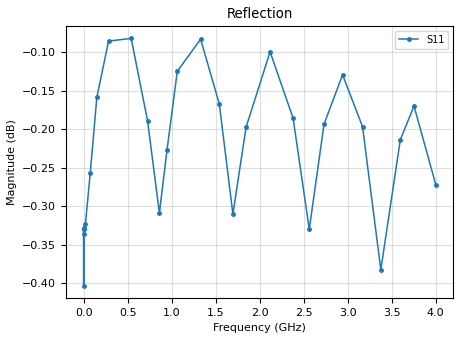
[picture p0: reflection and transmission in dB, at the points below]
#  HZ  Z  MA  R  50.0
! Rohde & Schwarz ZVL
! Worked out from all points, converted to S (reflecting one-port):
!   1001 points, 100 kHz to 4 GHz, reference 50 ohm
!   lowest |S11| = -0.4 dB at 314.1 kHz (marker M1), VSWR 43.10, Z = 2.15e+03 - j27.6 ohm
!   phase of S11 starts at 0 deg and turns -4 deg over the sweep
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100000  52.66 0.9
314067.1  43.09 -0.7
376060.3  52.97 -1.9
1414214  51.62 0.0
5318296  52.67 1.8
2e7  53.33 7.6
7.521206e7  61.89 24.0
1.497688e8  88.9 35.7
2.828427e8  182.2 26.0
5.39847e8  140.7 -48.3
7.263206e8  67.09 -43.0
8.605206e8  55.37 -10.1
9.466291e8  75.58 8.2
1.063659e9  138.9 3.3
1.328758e9  110.6 -58.0
1.541255e9  59.24 -55.2
1.695482e9  49.44 -28.0
1.845481e9  85.15 -14.6
2.118051e9  80.88 -62.4
2.379902e9  45.55 -60.8
2.563147e9  42.7 -35.8
2.731403e9  67.61 -41.2
2.941713e9  53.7 -66.4
3.168215e9  35.75 -66.1
3.376191e9  31.83 -45.5
3.59782e9  45.22 -56.2
3.753597e9  36.6 -69.0
4e9  24.73 -67.2
